One B-rep face of a CAD part: STEP entity #992.
In plain terms, the planar face has unit normal (0, 1, 0).
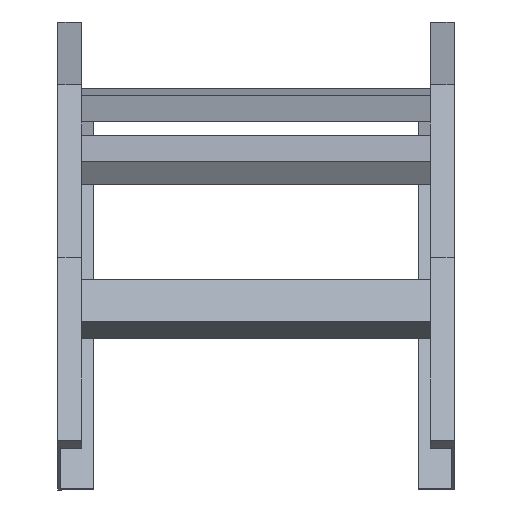
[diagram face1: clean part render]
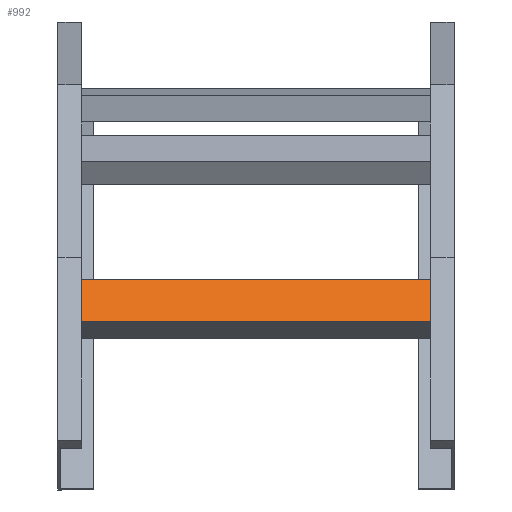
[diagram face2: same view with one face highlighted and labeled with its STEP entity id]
Its self-contained STEP definition (entity closure, numbers rounded to 3 decimals):
#105 = EDGE_CURVE ( 'NONE', #1143, #1269, #1129, .T. ) ;
#144 = CARTESIAN_POINT ( 'NONE',  ( 148., 20., -20.25 ) ) ;
#224 = CARTESIAN_POINT ( 'NONE',  ( 148., 20., 20.25 ) ) ;
#339 = VERTEX_POINT ( 'NONE', #681 ) ;
#404 = LINE ( 'NONE', #144, #916 ) ;
#486 = VECTOR ( 'NONE', #1170, 1000. ) ;
#490 = CARTESIAN_POINT ( 'NONE',  ( 148., 20., 20.25 ) ) ;
#496 = DIRECTION ( 'NONE',  ( 0., -1., 0. ) ) ;
#523 = ORIENTED_EDGE ( 'NONE', *, *, #1637, .F. ) ;
#524 = CARTESIAN_POINT ( 'NONE',  ( -148., 20., 20.25 ) ) ;
#565 = ORIENTED_EDGE ( 'NONE', *, *, #732, .T. ) ;
#675 = CARTESIAN_POINT ( 'NONE',  ( 148., 20., 20.25 ) ) ;
#681 = CARTESIAN_POINT ( 'NONE',  ( 148., 20., -20.25 ) ) ;
#708 = CARTESIAN_POINT ( 'NONE',  ( -148., 20., -20.25 ) ) ;
#732 = EDGE_CURVE ( 'NONE', #1219, #1269, #909, .T. ) ;
#778 = ORIENTED_EDGE ( 'NONE', *, *, #872, .T. ) ;
#804 = DIRECTION ( 'NONE',  ( 0., 0., 1. ) ) ;
#849 = FACE_OUTER_BOUND ( 'NONE', #1089, .T. ) ;
#872 = EDGE_CURVE ( 'NONE', #339, #1219, #404, .T. ) ;
#909 = LINE ( 'NONE', #1418, #1601 ) ;
#916 = VECTOR ( 'NONE', #1584, 1000. ) ;
#992 = ADVANCED_FACE ( 'NONE', ( #849 ), #1371, .F. ) ;
#1089 = EDGE_LOOP ( 'NONE', ( #565, #1536, #523, #778 ) ) ;
#1102 = DIRECTION ( 'NONE',  ( 0., 0., -1. ) ) ;
#1129 = LINE ( 'NONE', #1663, #1439 ) ;
#1143 = VERTEX_POINT ( 'NONE', #490 ) ;
#1170 = DIRECTION ( 'NONE',  ( 0., 0., 1. ) ) ;
#1219 = VERTEX_POINT ( 'NONE', #708 ) ;
#1269 = VERTEX_POINT ( 'NONE', #524 ) ;
#1271 = DIRECTION ( 'NONE',  ( -1., 0., 0. ) ) ;
#1371 = PLANE ( 'NONE',  #1514 ) ;
#1418 = CARTESIAN_POINT ( 'NONE',  ( -148., 20., 20.25 ) ) ;
#1439 = VECTOR ( 'NONE', #1271, 1000. ) ;
#1514 = AXIS2_PLACEMENT_3D ( 'NONE', #224, #496, #1102 ) ;
#1536 = ORIENTED_EDGE ( 'NONE', *, *, #105, .F. ) ;
#1541 = LINE ( 'NONE', #675, #486 ) ;
#1584 = DIRECTION ( 'NONE',  ( -1., 0., 0. ) ) ;
#1601 = VECTOR ( 'NONE', #804, 1000. ) ;
#1637 = EDGE_CURVE ( 'NONE', #339, #1143, #1541, .T. ) ;
#1663 = CARTESIAN_POINT ( 'NONE',  ( 148., 20., 20.25 ) ) ;
